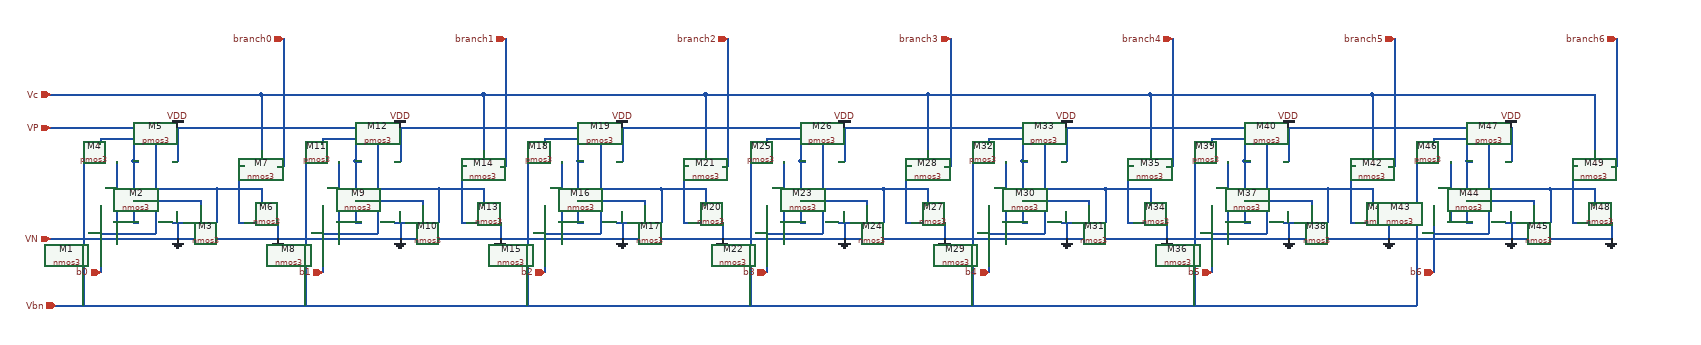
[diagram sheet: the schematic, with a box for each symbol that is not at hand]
v {xschem version=2.9.9 file_version=1.2 }
G {}
K {}
V {}
S {}
E {}
N 730 -820 730 -810 { lab=#net1}
N 730 -820 780 -820 { lab=#net1}
N 760 -780 760 -670 { lab=#net2}
N 700 -780 700 -670 { lab=Vbn}
N 730 -700 730 -580 { lab=b0}
N 730 -650 830 -650 { lab=b0}
N 830 -700 830 -650 { lab=b0}
N 790 -670 800 -670 { lab=#net1}
N 790 -780 800 -780 { lab=#net1}
N 790 -820 790 -780 { lab=#net1}
N 780 -820 790 -820 { lab=#net1}
N 790 -780 790 -670 { lab=#net1}
N 830 -810 830 -700 { lab=b0}
N 860 -780 870 -780 { lab=VDD}
N 870 -840 870 -780 { lab=VDD}
N 910 -710 910 -700 { lab=#net1}
N 790 -710 910 -710 { lab=#net1}
N 940 -730 940 -670 { lab=#net2}
N 760 -730 940 -730 { lab=#net2}
N 860 -670 880 -670 { lab=GND}
N 870 -670 870 -640 { lab=GND}
N 980 -670 990 -670 { lab=#net3}
N 980 -770 980 -670 { lab=#net3}
N 980 -770 990 -770 { lab=#net3}
N 1050 -670 1050 -640 { lab=GND}
N 1050 -770 1060 -770 { lab=branch0}
N 1060 -1000 1060 -770 { lab=branch0}
N 1020 -710 1020 -700 { lab=#net2}
N 1020 -730 1020 -710 { lab=#net2}
N 940 -730 1020 -730 { lab=#net2}
N 640 -900 1020 -900 { lab=Vc}
N 650 -520 710 -520 { lab=Vbn}
N 710 -520 1150 -520 { lab=Vbn}
N 1020 -900 1140 -900 { lab=Vc}
N 1020 -900 1020 -800 { lab=Vc}
N 1130 -820 1130 -810 { lab=#net4}
N 1130 -820 1180 -820 { lab=#net4}
N 1160 -780 1160 -670 { lab=#net5}
N 1100 -780 1100 -670 { lab=Vbn}
N 1130 -700 1130 -580 { lab=b1}
N 1130 -650 1230 -650 { lab=b1}
N 1230 -700 1230 -650 { lab=b1}
N 1190 -670 1200 -670 { lab=#net4}
N 1190 -780 1200 -780 { lab=#net4}
N 1190 -820 1190 -780 { lab=#net4}
N 1180 -820 1190 -820 { lab=#net4}
N 1190 -780 1190 -670 { lab=#net4}
N 1230 -810 1230 -700 { lab=b1}
N 1260 -780 1270 -780 { lab=VDD}
N 1270 -840 1270 -780 { lab=VDD}
N 1310 -710 1310 -700 { lab=#net4}
N 1190 -710 1310 -710 { lab=#net4}
N 1340 -730 1340 -670 { lab=#net5}
N 1160 -730 1340 -730 { lab=#net5}
N 1260 -670 1280 -670 { lab=GND}
N 1270 -670 1270 -640 { lab=GND}
N 1380 -670 1390 -670 { lab=#net6}
N 1380 -770 1380 -670 { lab=#net6}
N 1380 -770 1390 -770 { lab=#net6}
N 1450 -670 1450 -640 { lab=GND}
N 1450 -770 1460 -770 { lab=branch1}
N 1420 -710 1420 -700 { lab=#net5}
N 1420 -730 1420 -710 { lab=#net5}
N 1340 -730 1420 -730 { lab=#net5}
N 1420 -900 1420 -800 { lab=Vc}
N 1140 -900 1420 -900 { lab=Vc}
N 1460 -1000 1460 -770 { lab=branch1}
N 1150 -520 1510 -520 { lab=Vbn}
N 1420 -900 1500 -900 { lab=Vc}
N 1530 -820 1530 -810 { lab=#net7}
N 1530 -820 1580 -820 { lab=#net7}
N 1560 -780 1560 -670 { lab=#net8}
N 1500 -780 1500 -670 { lab=Vbn}
N 1530 -700 1530 -580 { lab=b2}
N 1530 -650 1630 -650 { lab=b2}
N 1630 -700 1630 -650 { lab=b2}
N 1590 -670 1600 -670 { lab=#net7}
N 1590 -780 1600 -780 { lab=#net7}
N 1590 -820 1590 -780 { lab=#net7}
N 1580 -820 1590 -820 { lab=#net7}
N 1590 -780 1590 -670 { lab=#net7}
N 1630 -810 1630 -700 { lab=b2}
N 1660 -780 1670 -780 { lab=VDD}
N 1670 -840 1670 -780 { lab=VDD}
N 1710 -710 1710 -700 { lab=#net7}
N 1590 -710 1710 -710 { lab=#net7}
N 1740 -730 1740 -670 { lab=#net8}
N 1560 -730 1740 -730 { lab=#net8}
N 1660 -670 1680 -670 { lab=GND}
N 1670 -670 1670 -640 { lab=GND}
N 1780 -670 1790 -670 { lab=#net9}
N 1780 -770 1780 -670 { lab=#net9}
N 1780 -770 1790 -770 { lab=#net9}
N 1850 -670 1850 -640 { lab=GND}
N 1850 -770 1860 -770 { lab=branch2}
N 1860 -1000 1860 -770 { lab=branch2}
N 1820 -710 1820 -700 { lab=#net8}
N 1820 -730 1820 -710 { lab=#net8}
N 1740 -730 1820 -730 { lab=#net8}
N 1510 -520 1950 -520 { lab=Vbn}
N 1820 -900 1940 -900 { lab=Vc}
N 1820 -900 1820 -800 { lab=Vc}
N 1930 -820 1930 -810 { lab=#net10}
N 1930 -820 1980 -820 { lab=#net10}
N 1960 -780 1960 -670 { lab=#net11}
N 1900 -780 1900 -670 { lab=Vbn}
N 1930 -700 1930 -580 { lab=b3}
N 1930 -650 2030 -650 { lab=b3}
N 2030 -700 2030 -650 { lab=b3}
N 1990 -670 2000 -670 { lab=#net10}
N 1990 -780 2000 -780 { lab=#net10}
N 1990 -820 1990 -780 { lab=#net10}
N 1980 -820 1990 -820 { lab=#net10}
N 1990 -780 1990 -670 { lab=#net10}
N 2030 -810 2030 -700 { lab=b3}
N 2060 -780 2070 -780 { lab=VDD}
N 2070 -840 2070 -780 { lab=VDD}
N 2110 -710 2110 -700 { lab=#net10}
N 1990 -710 2110 -710 { lab=#net10}
N 2140 -730 2140 -670 { lab=#net11}
N 1960 -730 2140 -730 { lab=#net11}
N 2060 -670 2080 -670 { lab=GND}
N 2070 -670 2070 -640 { lab=GND}
N 2180 -670 2190 -670 { lab=#net12}
N 2180 -770 2180 -670 { lab=#net12}
N 2180 -770 2190 -770 { lab=#net12}
N 2250 -670 2250 -640 { lab=GND}
N 2250 -770 2260 -770 { lab=branch3}
N 2220 -710 2220 -700 { lab=#net11}
N 2220 -730 2220 -710 { lab=#net11}
N 2140 -730 2220 -730 { lab=#net11}
N 2220 -900 2220 -800 { lab=Vc}
N 1940 -900 2220 -900 { lab=Vc}
N 2260 -1000 2260 -770 { lab=branch3}
N 1950 -520 2310 -520 { lab=Vbn}
N 2220 -900 2300 -900 { lab=Vc}
N 1500 -900 1820 -900 { lab=Vc}
N 2330 -820 2330 -810 { lab=#net13}
N 2330 -820 2380 -820 { lab=#net13}
N 2360 -780 2360 -670 { lab=#net14}
N 2300 -780 2300 -670 { lab=Vbn}
N 2330 -700 2330 -580 { lab=b4}
N 2330 -650 2430 -650 { lab=b4}
N 2430 -700 2430 -650 { lab=b4}
N 2390 -670 2400 -670 { lab=#net13}
N 2390 -780 2400 -780 { lab=#net13}
N 2390 -820 2390 -780 { lab=#net13}
N 2380 -820 2390 -820 { lab=#net13}
N 2390 -780 2390 -670 { lab=#net13}
N 2430 -810 2430 -700 { lab=b4}
N 2460 -780 2470 -780 { lab=VDD}
N 2470 -840 2470 -780 { lab=VDD}
N 2510 -710 2510 -700 { lab=#net13}
N 2390 -710 2510 -710 { lab=#net13}
N 2540 -730 2540 -670 { lab=#net14}
N 2360 -730 2540 -730 { lab=#net14}
N 2460 -670 2480 -670 { lab=GND}
N 2470 -670 2470 -640 { lab=GND}
N 2580 -670 2590 -670 { lab=#net15}
N 2580 -770 2580 -670 { lab=#net15}
N 2580 -770 2590 -770 { lab=#net15}
N 2650 -670 2650 -640 { lab=GND}
N 2650 -770 2660 -770 { lab=branch4}
N 2620 -710 2620 -700 { lab=#net14}
N 2620 -730 2620 -710 { lab=#net14}
N 2540 -730 2620 -730 { lab=#net14}
N 2620 -900 2620 -800 { lab=Vc}
N 2340 -900 2620 -900 { lab=Vc}
N 2660 -1000 2660 -770 { lab=branch4}
N 2350 -520 2710 -520 { lab=Vbn}
N 2620 -900 2700 -900 { lab=Vc}
N 2730 -820 2730 -810 { lab=#net16}
N 2730 -820 2780 -820 { lab=#net16}
N 2760 -780 2760 -670 { lab=#net17}
N 2700 -780 2700 -670 { lab=Vbn}
N 2730 -700 2730 -580 { lab=b5}
N 2730 -650 2830 -650 { lab=b5}
N 2830 -700 2830 -650 { lab=b5}
N 2790 -670 2800 -670 { lab=#net16}
N 2790 -780 2800 -780 { lab=#net16}
N 2790 -820 2790 -780 { lab=#net16}
N 2780 -820 2790 -820 { lab=#net16}
N 2790 -780 2790 -670 { lab=#net16}
N 2830 -810 2830 -700 { lab=b5}
N 2860 -780 2870 -780 { lab=VDD}
N 2870 -840 2870 -780 { lab=VDD}
N 2910 -710 2910 -700 { lab=#net16}
N 2790 -710 2910 -710 { lab=#net16}
N 2940 -730 2940 -670 { lab=#net17}
N 2760 -730 2940 -730 { lab=#net17}
N 2860 -670 2880 -670 { lab=GND}
N 2870 -670 2870 -640 { lab=GND}
N 2980 -670 2990 -670 { lab=#net18}
N 2980 -770 2980 -670 { lab=#net18}
N 2980 -770 2990 -770 { lab=#net18}
N 3050 -670 3050 -640 { lab=GND}
N 3050 -770 3060 -770 { lab=branch5}
N 3060 -1000 3060 -770 { lab=branch5}
N 3020 -710 3020 -700 { lab=#net17}
N 3020 -730 3020 -710 { lab=#net17}
N 2940 -730 3020 -730 { lab=#net17}
N 3020 -900 3140 -900 { lab=Vc}
N 3020 -900 3020 -800 { lab=Vc}
N 3130 -820 3130 -810 { lab=#net19}
N 3130 -820 3180 -820 { lab=#net19}
N 3160 -780 3160 -670 { lab=#net20}
N 3100 -780 3100 -670 { lab=Vbn}
N 3130 -700 3130 -580 { lab=b6}
N 3130 -650 3230 -650 { lab=b6}
N 3230 -700 3230 -650 { lab=b6}
N 3190 -670 3200 -670 { lab=#net19}
N 3190 -780 3200 -780 { lab=#net19}
N 3190 -820 3190 -780 { lab=#net19}
N 3180 -820 3190 -820 { lab=#net19}
N 3190 -780 3190 -670 { lab=#net19}
N 3230 -810 3230 -700 { lab=b6}
N 3260 -780 3270 -780 { lab=VDD}
N 3270 -840 3270 -780 { lab=VDD}
N 3310 -710 3310 -700 { lab=#net19}
N 3190 -710 3310 -710 { lab=#net19}
N 3340 -730 3340 -670 { lab=#net20}
N 3160 -730 3340 -730 { lab=#net20}
N 3260 -670 3280 -670 { lab=GND}
N 3270 -670 3270 -640 { lab=GND}
N 3380 -670 3390 -670 { lab=#net21}
N 3380 -770 3380 -670 { lab=#net21}
N 3380 -770 3390 -770 { lab=#net21}
N 3450 -670 3450 -640 { lab=GND}
N 3450 -770 3460 -770 { lab=branch6}
N 3420 -710 3420 -700 { lab=#net20}
N 3420 -730 3420 -710 { lab=#net20}
N 3340 -730 3420 -730 { lab=#net20}
N 3420 -900 3420 -800 { lab=Vc}
N 3140 -900 3420 -900 { lab=Vc}
N 3460 -1000 3460 -770 { lab=branch6}
N 2700 -900 3020 -900 { lab=Vc}
N 2310 -520 2350 -520 { lab=Vbn}
N 2300 -900 2340 -900 { lab=Vc}
N 700 -670 700 -520 { lab=Vbn}
N 1100 -670 1100 -520 { lab=Vbn}
N 1500 -670 1500 -520 { lab=Vbn}
N 1900 -670 1900 -520 { lab=Vbn}
N 2300 -670 2300 -520 { lab=Vbn}
N 2700 -670 2700 -520 { lab=Vbn}
N 3100 -670 3100 -520 { lab=Vbn}
N 2710 -520 3100 -520 { lab=Vbn}
N 640 -840 3270 -840 { lab=VP}
N 640 -640 3450 -640 { lab=VN}
C {madvlsi/nmos3.sym} 730 -670 1 0 {name=M1
L=0.3
W=3.15
body=GND
nf=1
mult=1
ad="'int((nf+1)/2) * W/nf * 0.29'" 
pd="'2*int((nf+1)/2) * (W/nf + 0.29)'"
as="'int((nf+2)/2) * W/nf * 0.29'" 
ps="'2*int((nf+2)/2) * (W/nf + 0.29)'"
nrd="'0.29 / W'" nrs="'0.29 / W'"
sa=0 sb=0 sd=0
model=nfet_01v8
spiceprefix=X
}
C {madvlsi/nmos3.sym} 830 -670 1 0 {name=M2
L=0.3
W=3.15
body=GND
nf=1
mult=1
ad="'int((nf+1)/2) * W/nf * 0.29'" 
pd="'2*int((nf+1)/2) * (W/nf + 0.29)'"
as="'int((nf+2)/2) * W/nf * 0.29'" 
ps="'2*int((nf+2)/2) * (W/nf + 0.29)'"
nrd="'0.29 / W'" nrs="'0.29 / W'"
sa=0 sb=0 sd=0
model=nfet_01v8
spiceprefix=X
}
C {madvlsi/nmos3.sym} 910 -670 1 0 {name=M3
L=0.3
W=3.15
body=GND
nf=1
mult=1
ad="'int((nf+1)/2) * W/nf * 0.29'" 
pd="'2*int((nf+1)/2) * (W/nf + 0.29)'"
as="'int((nf+2)/2) * W/nf * 0.29'" 
ps="'2*int((nf+2)/2) * (W/nf + 0.29)'"
nrd="'0.29 / W'" nrs="'0.29 / W'"
sa=0 sb=0 sd=0
model=nfet_01v8
spiceprefix=X
}
C {madvlsi/pmos3.sym} 730 -780 1 0 {name=M4
L=0.15
W=1
body=VDD
nf=1
mult=1
ad="'int((nf+1)/2) * W/nf * 0.29'" 
pd="'2*int((nf+1)/2) * (W/nf + 0.29)'"
as="'int((nf+2)/2) * W/nf * 0.29'" 
ps="'2*int((nf+2)/2) * (W/nf + 0.29)'"
nrd="'0.29 / W'" nrs="'0.29 / W'"
sa=0 sb=0 sd=0
model=pfet_01v8
spiceprefix=X
}
C {madvlsi/pmos3.sym} 830 -780 1 0 {name=M5
L=0.15
W=1
body=VDD
nf=1
mult=1
ad="'int((nf+1)/2) * W/nf * 0.29'" 
pd="'2*int((nf+1)/2) * (W/nf + 0.29)'"
as="'int((nf+2)/2) * W/nf * 0.29'" 
ps="'2*int((nf+2)/2) * (W/nf + 0.29)'"
nrd="'0.29 / W'" nrs="'0.29 / W'"
sa=0 sb=0 sd=0
model=pfet_01v8
spiceprefix=X
}
C {madvlsi/gnd.sym} 870 -640 0 0 {name=l1 lab=GND}
C {madvlsi/vdd.sym} 870 -840 0 0 {name=l2 lab=VDD}
C {madvlsi/nmos3.sym} 1020 -670 1 0 {name=M6
L=0.5
W=1.4
body=GND
nf=1
mult=1
ad="'int((nf+1)/2) * W/nf * 0.29'" 
pd="'2*int((nf+1)/2) * (W/nf + 0.29)'"
as="'int((nf+2)/2) * W/nf * 0.29'" 
ps="'2*int((nf+2)/2) * (W/nf + 0.29)'"
nrd="'0.29 / W'" nrs="'0.29 / W'"
sa=0 sb=0 sd=0
model=nfet_01v8
spiceprefix=X
}
C {madvlsi/nmos3.sym} 1020 -770 1 0 {name=M7
L=0.5
W=1.4
body=GND
nf=1
mult=1
ad="'int((nf+1)/2) * W/nf * 0.29'" 
pd="'2*int((nf+1)/2) * (W/nf + 0.29)'"
as="'int((nf+2)/2) * W/nf * 0.29'" 
ps="'2*int((nf+2)/2) * (W/nf + 0.29)'"
nrd="'0.29 / W'" nrs="'0.29 / W'"
sa=0 sb=0 sd=0
model=nfet_01v8
spiceprefix=X
}
C {madvlsi/gnd.sym} 1050 -640 0 0 {name=l3 lab=GND}
C {devices/ipin.sym} 640 -900 0 0 {name=p1 lab=Vc}
C {devices/ipin.sym} 650 -520 0 0 {name=p2 lab=Vbn}
C {devices/ipin.sym} 730 -580 3 0 {name=p3 lab=b0}
C {devices/iopin.sym} 1060 -1000 3 0 {name=p4 lab=branch0}
C {madvlsi/nmos3.sym} 1130 -670 1 0 {name=M8
L=0.3
W=3.15
body=GND
nf=1
mult=1
ad="'int((nf+1)/2) * W/nf * 0.29'" 
pd="'2*int((nf+1)/2) * (W/nf + 0.29)'"
as="'int((nf+2)/2) * W/nf * 0.29'" 
ps="'2*int((nf+2)/2) * (W/nf + 0.29)'"
nrd="'0.29 / W'" nrs="'0.29 / W'"
sa=0 sb=0 sd=0
model=nfet_01v8
spiceprefix=X
}
C {madvlsi/nmos3.sym} 1230 -670 1 0 {name=M9
L=0.3
W=3.15
body=GND
nf=1
mult=1
ad="'int((nf+1)/2) * W/nf * 0.29'" 
pd="'2*int((nf+1)/2) * (W/nf + 0.29)'"
as="'int((nf+2)/2) * W/nf * 0.29'" 
ps="'2*int((nf+2)/2) * (W/nf + 0.29)'"
nrd="'0.29 / W'" nrs="'0.29 / W'"
sa=0 sb=0 sd=0
model=nfet_01v8
spiceprefix=X
}
C {madvlsi/nmos3.sym} 1310 -670 1 0 {name=M10
L=0.3
W=3.15
body=GND
nf=1
mult=1
ad="'int((nf+1)/2) * W/nf * 0.29'" 
pd="'2*int((nf+1)/2) * (W/nf + 0.29)'"
as="'int((nf+2)/2) * W/nf * 0.29'" 
ps="'2*int((nf+2)/2) * (W/nf + 0.29)'"
nrd="'0.29 / W'" nrs="'0.29 / W'"
sa=0 sb=0 sd=0
model=nfet_01v8
spiceprefix=X
}
C {madvlsi/pmos3.sym} 1130 -780 1 0 {name=M11
L=0.15
W=1
body=VDD
nf=1
mult=1
ad="'int((nf+1)/2) * W/nf * 0.29'" 
pd="'2*int((nf+1)/2) * (W/nf + 0.29)'"
as="'int((nf+2)/2) * W/nf * 0.29'" 
ps="'2*int((nf+2)/2) * (W/nf + 0.29)'"
nrd="'0.29 / W'" nrs="'0.29 / W'"
sa=0 sb=0 sd=0
model=pfet_01v8
spiceprefix=X
}
C {madvlsi/pmos3.sym} 1230 -780 1 0 {name=M12
L=0.15
W=1
body=VDD
nf=1
mult=1
ad="'int((nf+1)/2) * W/nf * 0.29'" 
pd="'2*int((nf+1)/2) * (W/nf + 0.29)'"
as="'int((nf+2)/2) * W/nf * 0.29'" 
ps="'2*int((nf+2)/2) * (W/nf + 0.29)'"
nrd="'0.29 / W'" nrs="'0.29 / W'"
sa=0 sb=0 sd=0
model=pfet_01v8
spiceprefix=X
}
C {madvlsi/gnd.sym} 1270 -640 0 0 {name=l4 lab=GND}
C {madvlsi/vdd.sym} 1270 -840 0 0 {name=l5 lab=VDD}
C {madvlsi/nmos3.sym} 1420 -670 1 0 {name=M13
L=0.5
W=1.4
body=GND
nf=1
mult=1
ad="'int((nf+1)/2) * W/nf * 0.29'" 
pd="'2*int((nf+1)/2) * (W/nf + 0.29)'"
as="'int((nf+2)/2) * W/nf * 0.29'" 
ps="'2*int((nf+2)/2) * (W/nf + 0.29)'"
nrd="'0.29 / W'" nrs="'0.29 / W'"
sa=0 sb=0 sd=0
model=nfet_01v8
spiceprefix=X
}
C {madvlsi/nmos3.sym} 1420 -770 1 0 {name=M14
L=0.5
W=1.4
body=GND
nf=1
mult=1
ad="'int((nf+1)/2) * W/nf * 0.29'" 
pd="'2*int((nf+1)/2) * (W/nf + 0.29)'"
as="'int((nf+2)/2) * W/nf * 0.29'" 
ps="'2*int((nf+2)/2) * (W/nf + 0.29)'"
nrd="'0.29 / W'" nrs="'0.29 / W'"
sa=0 sb=0 sd=0
model=nfet_01v8
spiceprefix=X
}
C {madvlsi/gnd.sym} 1450 -640 0 0 {name=l6 lab=GND}
C {devices/ipin.sym} 1130 -580 3 0 {name=p5 lab=b1}
C {devices/iopin.sym} 1460 -1000 3 0 {name=p6 lab=branch1}
C {madvlsi/nmos3.sym} 1530 -670 1 0 {name=M15
L=0.3
W=3.15
body=GND
nf=1
mult=1
ad="'int((nf+1)/2) * W/nf * 0.29'" 
pd="'2*int((nf+1)/2) * (W/nf + 0.29)'"
as="'int((nf+2)/2) * W/nf * 0.29'" 
ps="'2*int((nf+2)/2) * (W/nf + 0.29)'"
nrd="'0.29 / W'" nrs="'0.29 / W'"
sa=0 sb=0 sd=0
model=nfet_01v8
spiceprefix=X
}
C {madvlsi/nmos3.sym} 1630 -670 1 0 {name=M16
L=0.3
W=3.15
body=GND
nf=1
mult=1
ad="'int((nf+1)/2) * W/nf * 0.29'" 
pd="'2*int((nf+1)/2) * (W/nf + 0.29)'"
as="'int((nf+2)/2) * W/nf * 0.29'" 
ps="'2*int((nf+2)/2) * (W/nf + 0.29)'"
nrd="'0.29 / W'" nrs="'0.29 / W'"
sa=0 sb=0 sd=0
model=nfet_01v8
spiceprefix=X
}
C {madvlsi/nmos3.sym} 1710 -670 1 0 {name=M17
L=0.3
W=3.15
body=GND
nf=1
mult=1
ad="'int((nf+1)/2) * W/nf * 0.29'" 
pd="'2*int((nf+1)/2) * (W/nf + 0.29)'"
as="'int((nf+2)/2) * W/nf * 0.29'" 
ps="'2*int((nf+2)/2) * (W/nf + 0.29)'"
nrd="'0.29 / W'" nrs="'0.29 / W'"
sa=0 sb=0 sd=0
model=nfet_01v8
spiceprefix=X
}
C {madvlsi/pmos3.sym} 1530 -780 1 0 {name=M18
L=0.15
W=1
body=VDD
nf=1
mult=1
ad="'int((nf+1)/2) * W/nf * 0.29'" 
pd="'2*int((nf+1)/2) * (W/nf + 0.29)'"
as="'int((nf+2)/2) * W/nf * 0.29'" 
ps="'2*int((nf+2)/2) * (W/nf + 0.29)'"
nrd="'0.29 / W'" nrs="'0.29 / W'"
sa=0 sb=0 sd=0
model=pfet_01v8
spiceprefix=X
}
C {madvlsi/pmos3.sym} 1630 -780 1 0 {name=M19
L=0.15
W=1
body=VDD
nf=1
mult=1
ad="'int((nf+1)/2) * W/nf * 0.29'" 
pd="'2*int((nf+1)/2) * (W/nf + 0.29)'"
as="'int((nf+2)/2) * W/nf * 0.29'" 
ps="'2*int((nf+2)/2) * (W/nf + 0.29)'"
nrd="'0.29 / W'" nrs="'0.29 / W'"
sa=0 sb=0 sd=0
model=pfet_01v8
spiceprefix=X
}
C {madvlsi/gnd.sym} 1670 -640 0 0 {name=l7 lab=GND}
C {madvlsi/vdd.sym} 1670 -840 0 0 {name=l8 lab=VDD}
C {madvlsi/nmos3.sym} 1820 -670 1 0 {name=M20
L=0.5
W=1.4
body=GND
nf=1
mult=1
ad="'int((nf+1)/2) * W/nf * 0.29'" 
pd="'2*int((nf+1)/2) * (W/nf + 0.29)'"
as="'int((nf+2)/2) * W/nf * 0.29'" 
ps="'2*int((nf+2)/2) * (W/nf + 0.29)'"
nrd="'0.29 / W'" nrs="'0.29 / W'"
sa=0 sb=0 sd=0
model=nfet_01v8
spiceprefix=X
}
C {madvlsi/nmos3.sym} 1820 -770 1 0 {name=M21
L=0.5
W=1.4
body=GND
nf=1
mult=1
ad="'int((nf+1)/2) * W/nf * 0.29'" 
pd="'2*int((nf+1)/2) * (W/nf + 0.29)'"
as="'int((nf+2)/2) * W/nf * 0.29'" 
ps="'2*int((nf+2)/2) * (W/nf + 0.29)'"
nrd="'0.29 / W'" nrs="'0.29 / W'"
sa=0 sb=0 sd=0
model=nfet_01v8
spiceprefix=X
}
C {madvlsi/gnd.sym} 1850 -640 0 0 {name=l9 lab=GND}
C {devices/ipin.sym} 1530 -580 3 0 {name=p7 lab=b2}
C {devices/iopin.sym} 1860 -1000 3 0 {name=p8 lab=branch2}
C {madvlsi/nmos3.sym} 1930 -670 1 0 {name=M22
L=0.3
W=3.15
body=GND
nf=1
mult=1
ad="'int((nf+1)/2) * W/nf * 0.29'" 
pd="'2*int((nf+1)/2) * (W/nf + 0.29)'"
as="'int((nf+2)/2) * W/nf * 0.29'" 
ps="'2*int((nf+2)/2) * (W/nf + 0.29)'"
nrd="'0.29 / W'" nrs="'0.29 / W'"
sa=0 sb=0 sd=0
model=nfet_01v8
spiceprefix=X
}
C {madvlsi/nmos3.sym} 2030 -670 1 0 {name=M23
L=0.3
W=3.15
body=GND
nf=1
mult=1
ad="'int((nf+1)/2) * W/nf * 0.29'" 
pd="'2*int((nf+1)/2) * (W/nf + 0.29)'"
as="'int((nf+2)/2) * W/nf * 0.29'" 
ps="'2*int((nf+2)/2) * (W/nf + 0.29)'"
nrd="'0.29 / W'" nrs="'0.29 / W'"
sa=0 sb=0 sd=0
model=nfet_01v8
spiceprefix=X
}
C {madvlsi/nmos3.sym} 2110 -670 1 0 {name=M24
L=0.3
W=3.15
body=GND
nf=1
mult=1
ad="'int((nf+1)/2) * W/nf * 0.29'" 
pd="'2*int((nf+1)/2) * (W/nf + 0.29)'"
as="'int((nf+2)/2) * W/nf * 0.29'" 
ps="'2*int((nf+2)/2) * (W/nf + 0.29)'"
nrd="'0.29 / W'" nrs="'0.29 / W'"
sa=0 sb=0 sd=0
model=nfet_01v8
spiceprefix=X
}
C {madvlsi/pmos3.sym} 1930 -780 1 0 {name=M25
L=0.15
W=1
body=VDD
nf=1
mult=1
ad="'int((nf+1)/2) * W/nf * 0.29'" 
pd="'2*int((nf+1)/2) * (W/nf + 0.29)'"
as="'int((nf+2)/2) * W/nf * 0.29'" 
ps="'2*int((nf+2)/2) * (W/nf + 0.29)'"
nrd="'0.29 / W'" nrs="'0.29 / W'"
sa=0 sb=0 sd=0
model=pfet_01v8
spiceprefix=X
}
C {madvlsi/pmos3.sym} 2030 -780 1 0 {name=M26
L=0.15
W=1
body=VDD
nf=1
mult=1
ad="'int((nf+1)/2) * W/nf * 0.29'" 
pd="'2*int((nf+1)/2) * (W/nf + 0.29)'"
as="'int((nf+2)/2) * W/nf * 0.29'" 
ps="'2*int((nf+2)/2) * (W/nf + 0.29)'"
nrd="'0.29 / W'" nrs="'0.29 / W'"
sa=0 sb=0 sd=0
model=pfet_01v8
spiceprefix=X
}
C {madvlsi/gnd.sym} 2070 -640 0 0 {name=l10 lab=GND}
C {madvlsi/vdd.sym} 2070 -840 0 0 {name=l11 lab=VDD}
C {madvlsi/nmos3.sym} 2220 -670 1 0 {name=M27
L=0.5
W=1.4
body=GND
nf=1
mult=1
ad="'int((nf+1)/2) * W/nf * 0.29'" 
pd="'2*int((nf+1)/2) * (W/nf + 0.29)'"
as="'int((nf+2)/2) * W/nf * 0.29'" 
ps="'2*int((nf+2)/2) * (W/nf + 0.29)'"
nrd="'0.29 / W'" nrs="'0.29 / W'"
sa=0 sb=0 sd=0
model=nfet_01v8
spiceprefix=X
}
C {madvlsi/nmos3.sym} 2220 -770 1 0 {name=M28
L=0.5
W=1.4
body=GND
nf=1
mult=1
ad="'int((nf+1)/2) * W/nf * 0.29'" 
pd="'2*int((nf+1)/2) * (W/nf + 0.29)'"
as="'int((nf+2)/2) * W/nf * 0.29'" 
ps="'2*int((nf+2)/2) * (W/nf + 0.29)'"
nrd="'0.29 / W'" nrs="'0.29 / W'"
sa=0 sb=0 sd=0
model=nfet_01v8
spiceprefix=X
}
C {madvlsi/gnd.sym} 2250 -640 0 0 {name=l12 lab=GND}
C {devices/ipin.sym} 1930 -580 3 0 {name=p9 lab=b3}
C {devices/iopin.sym} 2260 -1000 3 0 {name=p10 lab=branch3}
C {madvlsi/nmos3.sym} 2330 -670 1 0 {name=M29
L=0.3
W=3.15
body=GND
nf=1
mult=1
ad="'int((nf+1)/2) * W/nf * 0.29'" 
pd="'2*int((nf+1)/2) * (W/nf + 0.29)'"
as="'int((nf+2)/2) * W/nf * 0.29'" 
ps="'2*int((nf+2)/2) * (W/nf + 0.29)'"
nrd="'0.29 / W'" nrs="'0.29 / W'"
sa=0 sb=0 sd=0
model=nfet_01v8
spiceprefix=X
}
C {madvlsi/nmos3.sym} 2430 -670 1 0 {name=M30
L=0.3
W=3.15
body=GND
nf=1
mult=1
ad="'int((nf+1)/2) * W/nf * 0.29'" 
pd="'2*int((nf+1)/2) * (W/nf + 0.29)'"
as="'int((nf+2)/2) * W/nf * 0.29'" 
ps="'2*int((nf+2)/2) * (W/nf + 0.29)'"
nrd="'0.29 / W'" nrs="'0.29 / W'"
sa=0 sb=0 sd=0
model=nfet_01v8
spiceprefix=X
}
C {madvlsi/nmos3.sym} 2510 -670 1 0 {name=M31
L=0.3
W=3.15
body=GND
nf=1
mult=1
ad="'int((nf+1)/2) * W/nf * 0.29'" 
pd="'2*int((nf+1)/2) * (W/nf + 0.29)'"
as="'int((nf+2)/2) * W/nf * 0.29'" 
ps="'2*int((nf+2)/2) * (W/nf + 0.29)'"
nrd="'0.29 / W'" nrs="'0.29 / W'"
sa=0 sb=0 sd=0
model=nfet_01v8
spiceprefix=X
}
C {madvlsi/pmos3.sym} 2330 -780 1 0 {name=M32
L=0.15
W=1
body=VDD
nf=1
mult=1
ad="'int((nf+1)/2) * W/nf * 0.29'" 
pd="'2*int((nf+1)/2) * (W/nf + 0.29)'"
as="'int((nf+2)/2) * W/nf * 0.29'" 
ps="'2*int((nf+2)/2) * (W/nf + 0.29)'"
nrd="'0.29 / W'" nrs="'0.29 / W'"
sa=0 sb=0 sd=0
model=pfet_01v8
spiceprefix=X
}
C {madvlsi/pmos3.sym} 2430 -780 1 0 {name=M33
L=0.15
W=1
body=VDD
nf=1
mult=1
ad="'int((nf+1)/2) * W/nf * 0.29'" 
pd="'2*int((nf+1)/2) * (W/nf + 0.29)'"
as="'int((nf+2)/2) * W/nf * 0.29'" 
ps="'2*int((nf+2)/2) * (W/nf + 0.29)'"
nrd="'0.29 / W'" nrs="'0.29 / W'"
sa=0 sb=0 sd=0
model=pfet_01v8
spiceprefix=X
}
C {madvlsi/gnd.sym} 2470 -640 0 0 {name=l13 lab=GND}
C {madvlsi/vdd.sym} 2470 -840 0 0 {name=l14 lab=VDD}
C {madvlsi/nmos3.sym} 2620 -670 1 0 {name=M34
L=0.5
W=1.4
body=GND
nf=1
mult=1
ad="'int((nf+1)/2) * W/nf * 0.29'" 
pd="'2*int((nf+1)/2) * (W/nf + 0.29)'"
as="'int((nf+2)/2) * W/nf * 0.29'" 
ps="'2*int((nf+2)/2) * (W/nf + 0.29)'"
nrd="'0.29 / W'" nrs="'0.29 / W'"
sa=0 sb=0 sd=0
model=nfet_01v8
spiceprefix=X
}
C {madvlsi/nmos3.sym} 2620 -770 1 0 {name=M35
L=0.5
W=1.4
body=GND
nf=1
mult=1
ad="'int((nf+1)/2) * W/nf * 0.29'" 
pd="'2*int((nf+1)/2) * (W/nf + 0.29)'"
as="'int((nf+2)/2) * W/nf * 0.29'" 
ps="'2*int((nf+2)/2) * (W/nf + 0.29)'"
nrd="'0.29 / W'" nrs="'0.29 / W'"
sa=0 sb=0 sd=0
model=nfet_01v8
spiceprefix=X
}
C {madvlsi/gnd.sym} 2650 -640 0 0 {name=l15 lab=GND}
C {devices/ipin.sym} 2330 -580 3 0 {name=p11 lab=b4}
C {devices/iopin.sym} 2660 -1000 3 0 {name=p12 lab=branch4}
C {madvlsi/nmos3.sym} 2730 -670 1 0 {name=M36
L=0.3
W=3.15
body=GND
nf=1
mult=1
ad="'int((nf+1)/2) * W/nf * 0.29'" 
pd="'2*int((nf+1)/2) * (W/nf + 0.29)'"
as="'int((nf+2)/2) * W/nf * 0.29'" 
ps="'2*int((nf+2)/2) * (W/nf + 0.29)'"
nrd="'0.29 / W'" nrs="'0.29 / W'"
sa=0 sb=0 sd=0
model=nfet_01v8
spiceprefix=X
}
C {madvlsi/nmos3.sym} 2830 -670 1 0 {name=M37
L=0.3
W=3.15
body=GND
nf=1
mult=1
ad="'int((nf+1)/2) * W/nf * 0.29'" 
pd="'2*int((nf+1)/2) * (W/nf + 0.29)'"
as="'int((nf+2)/2) * W/nf * 0.29'" 
ps="'2*int((nf+2)/2) * (W/nf + 0.29)'"
nrd="'0.29 / W'" nrs="'0.29 / W'"
sa=0 sb=0 sd=0
model=nfet_01v8
spiceprefix=X
}
C {madvlsi/nmos3.sym} 2910 -670 1 0 {name=M38
L=0.3
W=3.15
body=GND
nf=1
mult=1
ad="'int((nf+1)/2) * W/nf * 0.29'" 
pd="'2*int((nf+1)/2) * (W/nf + 0.29)'"
as="'int((nf+2)/2) * W/nf * 0.29'" 
ps="'2*int((nf+2)/2) * (W/nf + 0.29)'"
nrd="'0.29 / W'" nrs="'0.29 / W'"
sa=0 sb=0 sd=0
model=nfet_01v8
spiceprefix=X
}
C {madvlsi/pmos3.sym} 2730 -780 1 0 {name=M39
L=0.15
W=1
body=VDD
nf=1
mult=1
ad="'int((nf+1)/2) * W/nf * 0.29'" 
pd="'2*int((nf+1)/2) * (W/nf + 0.29)'"
as="'int((nf+2)/2) * W/nf * 0.29'" 
ps="'2*int((nf+2)/2) * (W/nf + 0.29)'"
nrd="'0.29 / W'" nrs="'0.29 / W'"
sa=0 sb=0 sd=0
model=pfet_01v8
spiceprefix=X
}
C {madvlsi/pmos3.sym} 2830 -780 1 0 {name=M40
L=0.15
W=1
body=VDD
nf=1
mult=1
ad="'int((nf+1)/2) * W/nf * 0.29'" 
pd="'2*int((nf+1)/2) * (W/nf + 0.29)'"
as="'int((nf+2)/2) * W/nf * 0.29'" 
ps="'2*int((nf+2)/2) * (W/nf + 0.29)'"
nrd="'0.29 / W'" nrs="'0.29 / W'"
sa=0 sb=0 sd=0
model=pfet_01v8
spiceprefix=X
}
C {madvlsi/gnd.sym} 2870 -640 0 0 {name=l16 lab=GND}
C {madvlsi/vdd.sym} 2870 -840 0 0 {name=l17 lab=VDD}
C {madvlsi/nmos3.sym} 3020 -670 1 0 {name=M41
L=0.5
W=1.4
body=GND
nf=1
mult=1
ad="'int((nf+1)/2) * W/nf * 0.29'" 
pd="'2*int((nf+1)/2) * (W/nf + 0.29)'"
as="'int((nf+2)/2) * W/nf * 0.29'" 
ps="'2*int((nf+2)/2) * (W/nf + 0.29)'"
nrd="'0.29 / W'" nrs="'0.29 / W'"
sa=0 sb=0 sd=0
model=nfet_01v8
spiceprefix=X
}
C {madvlsi/nmos3.sym} 3020 -770 1 0 {name=M42
L=0.5
W=1.4
body=GND
nf=1
mult=1
ad="'int((nf+1)/2) * W/nf * 0.29'" 
pd="'2*int((nf+1)/2) * (W/nf + 0.29)'"
as="'int((nf+2)/2) * W/nf * 0.29'" 
ps="'2*int((nf+2)/2) * (W/nf + 0.29)'"
nrd="'0.29 / W'" nrs="'0.29 / W'"
sa=0 sb=0 sd=0
model=nfet_01v8
spiceprefix=X
}
C {madvlsi/gnd.sym} 3050 -640 0 0 {name=l18 lab=GND}
C {devices/ipin.sym} 2730 -580 3 0 {name=p13 lab=b5}
C {devices/iopin.sym} 3060 -1000 3 0 {name=p14 lab=branch5}
C {madvlsi/nmos3.sym} 3130 -670 1 0 {name=M43
L=0.3
W=3.15
body=GND
nf=1
mult=1
ad="'int((nf+1)/2) * W/nf * 0.29'" 
pd="'2*int((nf+1)/2) * (W/nf + 0.29)'"
as="'int((nf+2)/2) * W/nf * 0.29'" 
ps="'2*int((nf+2)/2) * (W/nf + 0.29)'"
nrd="'0.29 / W'" nrs="'0.29 / W'"
sa=0 sb=0 sd=0
model=nfet_01v8
spiceprefix=X
}
C {madvlsi/nmos3.sym} 3230 -670 1 0 {name=M44
L=0.3
W=3.15
body=GND
nf=1
mult=1
ad="'int((nf+1)/2) * W/nf * 0.29'" 
pd="'2*int((nf+1)/2) * (W/nf + 0.29)'"
as="'int((nf+2)/2) * W/nf * 0.29'" 
ps="'2*int((nf+2)/2) * (W/nf + 0.29)'"
nrd="'0.29 / W'" nrs="'0.29 / W'"
sa=0 sb=0 sd=0
model=nfet_01v8
spiceprefix=X
}
C {madvlsi/nmos3.sym} 3310 -670 1 0 {name=M45
L=0.3
W=3.15
body=GND
nf=1
mult=1
ad="'int((nf+1)/2) * W/nf * 0.29'" 
pd="'2*int((nf+1)/2) * (W/nf + 0.29)'"
as="'int((nf+2)/2) * W/nf * 0.29'" 
ps="'2*int((nf+2)/2) * (W/nf + 0.29)'"
nrd="'0.29 / W'" nrs="'0.29 / W'"
sa=0 sb=0 sd=0
model=nfet_01v8
spiceprefix=X
}
C {madvlsi/pmos3.sym} 3130 -780 1 0 {name=M46
L=0.15
W=1
body=VDD
nf=1
mult=1
ad="'int((nf+1)/2) * W/nf * 0.29'" 
pd="'2*int((nf+1)/2) * (W/nf + 0.29)'"
as="'int((nf+2)/2) * W/nf * 0.29'" 
ps="'2*int((nf+2)/2) * (W/nf + 0.29)'"
nrd="'0.29 / W'" nrs="'0.29 / W'"
sa=0 sb=0 sd=0
model=pfet_01v8
spiceprefix=X
}
C {madvlsi/pmos3.sym} 3230 -780 1 0 {name=M47
L=0.15
W=1
body=VDD
nf=1
mult=1
ad="'int((nf+1)/2) * W/nf * 0.29'" 
pd="'2*int((nf+1)/2) * (W/nf + 0.29)'"
as="'int((nf+2)/2) * W/nf * 0.29'" 
ps="'2*int((nf+2)/2) * (W/nf + 0.29)'"
nrd="'0.29 / W'" nrs="'0.29 / W'"
sa=0 sb=0 sd=0
model=pfet_01v8
spiceprefix=X
}
C {madvlsi/gnd.sym} 3270 -640 0 0 {name=l19 lab=GND}
C {madvlsi/vdd.sym} 3270 -840 0 0 {name=l20 lab=VDD}
C {madvlsi/nmos3.sym} 3420 -670 1 0 {name=M48
L=0.5
W=1.4
body=GND
nf=1
mult=1
ad="'int((nf+1)/2) * W/nf * 0.29'" 
pd="'2*int((nf+1)/2) * (W/nf + 0.29)'"
as="'int((nf+2)/2) * W/nf * 0.29'" 
ps="'2*int((nf+2)/2) * (W/nf + 0.29)'"
nrd="'0.29 / W'" nrs="'0.29 / W'"
sa=0 sb=0 sd=0
model=nfet_01v8
spiceprefix=X
}
C {madvlsi/nmos3.sym} 3420 -770 1 0 {name=M49
L=0.5
W=1.4
body=GND
nf=1
mult=1
ad="'int((nf+1)/2) * W/nf * 0.29'" 
pd="'2*int((nf+1)/2) * (W/nf + 0.29)'"
as="'int((nf+2)/2) * W/nf * 0.29'" 
ps="'2*int((nf+2)/2) * (W/nf + 0.29)'"
nrd="'0.29 / W'" nrs="'0.29 / W'"
sa=0 sb=0 sd=0
model=nfet_01v8
spiceprefix=X
}
C {madvlsi/gnd.sym} 3450 -640 0 0 {name=l21 lab=GND}
C {devices/ipin.sym} 3130 -580 3 0 {name=p15 lab=b6}
C {devices/iopin.sym} 3460 -1000 3 0 {name=p16 lab=branch6}
C {devices/iopin.sym} 640 -840 2 0 {name=p17 lab=VP}
C {devices/iopin.sym} 640 -640 2 0 {name=p18 lab=VN}
